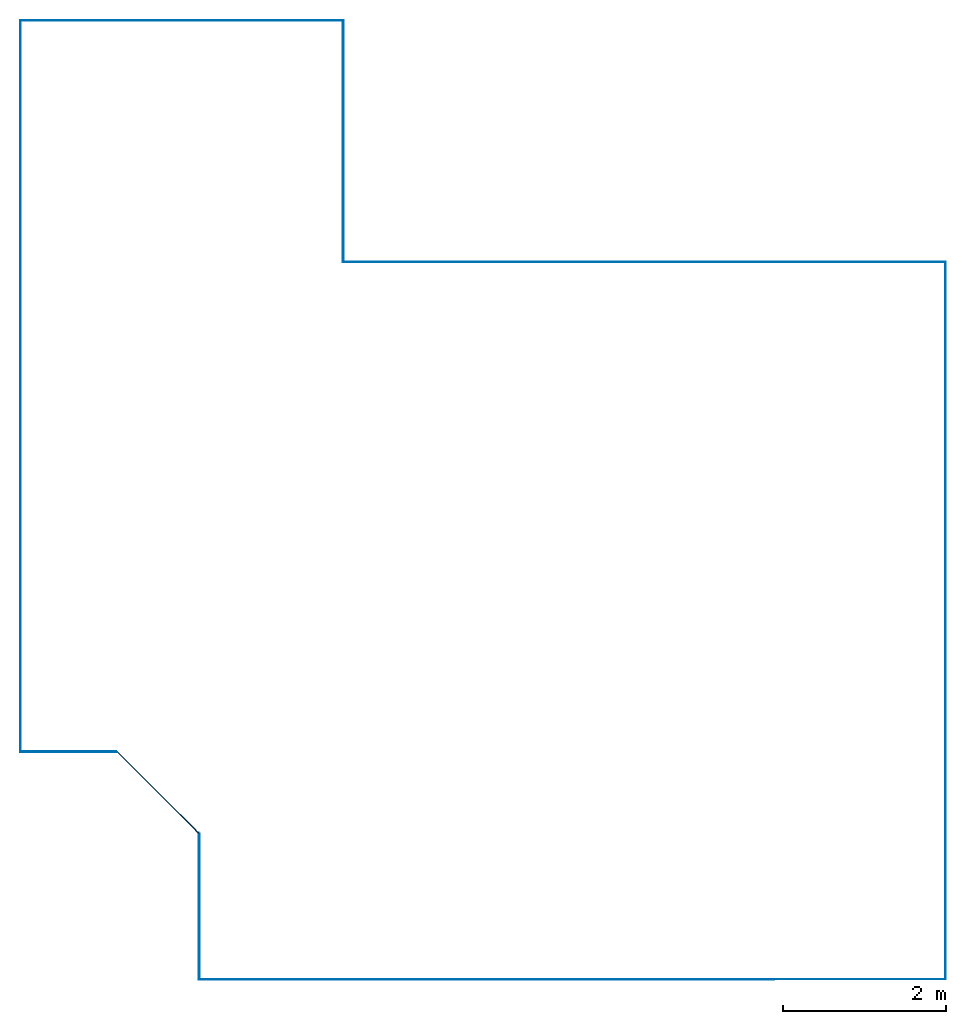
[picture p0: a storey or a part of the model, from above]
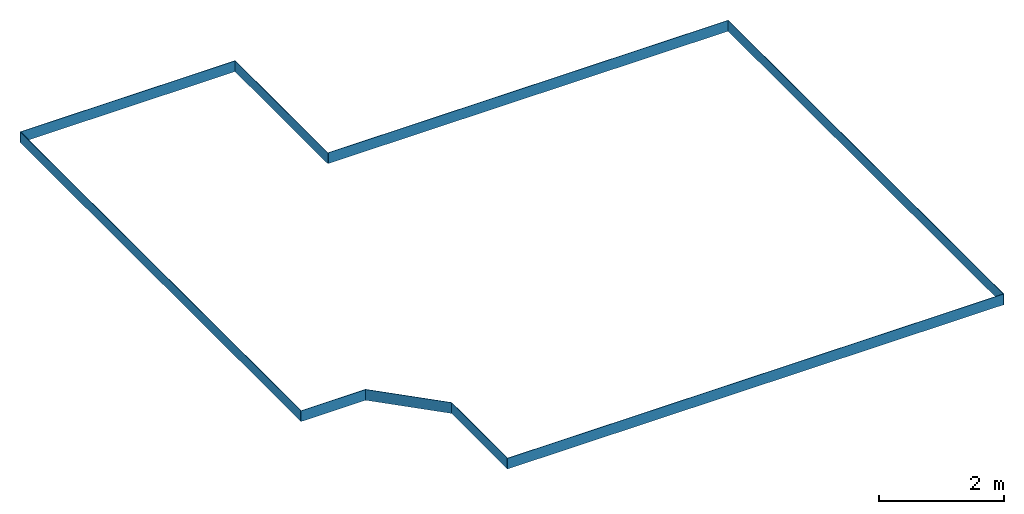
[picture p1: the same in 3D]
Properties of the parts of a building model (IFC2X3)

# File
Description: ViewDefinition [CoordinationView_V2.0], ExchangeRequirement [Architecture]
File name: Numéro du projet
Time: 2023-03-23T14:43:53+01:00
Written by: ODA SDAI 22.12
Made in: 23.0.11.19 - Exporter 23.0.11.19 - Interface utilisateur alternative 23.0.11.19

# IfcProject, Numéro du projet
LongName: Nom du projet; Phase: Etat du projet

# IfcSite, Default
RefLatitude: 48, 51, 23, 999633; RefLongitude: 2, 21, 3, 553905; RefElevation: 0 cm

# IfcBuilding
Pset_BuildingCommon - NumberOfStoreys: 4

# IfcBuildingStorey: Niveau:Ligne du Niveau (4)
Name | LongName | Elevation (cm)
0_Fondation | 0_Fondation | -98
-0.29_Dessous plancher | -0.29_Dessous plancher | -29
-0.08_Dessus plancher | -0.08_Dessus plancher | -8
2.57_Dessus dalle | 2.57_Dessus dalle | 257

# IfcBuildingElementProxy: 306233
In: 0_Fondation
Pset_ProvisionForVoid - Shape: Undefined; Depth: 114 cm

# IfcBuildingElementProxy: 306311
In: 0_Fondation
Pset_ProvisionForVoid - Shape: Undefined; Depth: 87 cm

# IfcBuildingElementProxy: 306359
In: 0_Fondation
Pset_ProvisionForVoid - Shape: Undefined; Depth: 67 cm

# IfcBuildingElementProxy: 306388
In: 0_Fondation
Pset_ProvisionForVoid - Shape: Undefined; Depth: 67 cm

# IfcBuildingElementProxy: 306447
In: 0_Fondation
Pset_ProvisionForVoid - Shape: Undefined; Depth: 346 cm

# IfcFooting: Semelle filante:Semelle 45 x 25 (9)
In: 0_Fondation
PredefinedType: STRIP_FOOTING; Material: Maçonnerie - Béton
Pset_QuantityTakeOff - Reference: Semelle filante:Semelle 45 x 25; sets with these values: 3
Name (Semelle filante:Semelle 45 x 25:...)
305962
305980
305998
306016
306030
306048
306066
306084
306102

# IfcFooting: Semelle filante:Semelle 45 x 25 refend (5)
In: 0_Fondation
PredefinedType: STRIP_FOOTING; Material: Maçonnerie - Béton
Pset_QuantityTakeOff - Reference: Semelle filante:Semelle 45 x 25 refend; sets with these values: 3
Name (Semelle filante:Semelle 45 x 25 refend:...)
306509
306563
306585
306607
306629

# IfcOpeningElement: Opening (19)
Name | In | Reference | sets with these values
Mur de base:Mur 20:300279 | -0.08_Dessus plancher | 1 Vantail - Droit blanc:140/90 | 2
Mur de base:Mur 20:300304 | -0.08_Dessus plancher | PF 1 Vantail - Droite blanc:80/210 | 2
Mur de base:Mur 20:300374 | -0.08_Dessus plancher | PF 2 Vantaux - Droits blanc:240/210 | 2
Mur de base:Mur 20:300374 | -0.08_Dessus plancher | PF 1 Vantail - Droite blanc:160/210 | 2
Mur de base:Mur 20:300374 | -0.08_Dessus plancher | PF 1 Vantail - Droite blanc:180/210 | 2
Mur de base:Mur 20:300423 | -0.08_Dessus plancher | PF 1 Vantail - Droite blanc:180/210 | 2
Mur de base:Mur 20:300423 | -0.08_Dessus plancher | 2 Vantaux coulissants - Droits blanc:140/80 | 2
2 x Mur de base:Mur 20:300475 | -0.08_Dessus plancher | 1 Vantail - Droit blanc:60/80 | 2
Mur de base:Mur 20:300475 | -0.08_Dessus plancher | 2 Vantaux coulissants - Droits blanc:140/80 | 2
Mur de base:Mur 20:300514 | -0.08_Dessus plancher | Porte d'entrée gris:90 x 215 cm | 2
Mur de base:Mur 20:300790 | -0.08_Dessus plancher | VLT17 Entrée:PP Avec moulures (0.90 m x 2.15 m) | 2
Sol:Plancher 12+4:302912:2 | 2.57_Dessus dalle | Sol:Plancher 12+4 | 2
Radier:Béton de propreté 5cm:306743:2 | 0_Fondation | Radier:Béton de propreté 5cm | 2
Mur de base:Mur 20:319389 | -0.08_Dessus plancher | PF 2 Vantaux - Droits blanc:240/210 | 2
Mur de base:Mur 20:319389 | -0.08_Dessus plancher | PF 1 Vantail - Droite blanc:160/210 | 2
Mur de base:Mur 20:319389 | -0.08_Dessus plancher | PF 1 Vantail - Droite blanc:180/210 | 2
Mur de base:Mur 20:300988 | -0.08_Dessus plancher
Mur de base:Mur 20:320650 | -0.08_Dessus plancher

# IfcSlab: Radier:Béton de propreté 5cm, Radier:Béton de propreté 5cm:306743:6
In: 0_Fondation
Type - PredefinedType: BASESLAB; Material: Maçonnerie - Béton(2) 5 cm
Type - Pset_SlabCommon - IsExternal: no
Pset_QuantityTakeOff - Reference: Radier:Béton de propreté 5cm; sets with these values: 2
Pset_SlabCommon - PitchAngle: 0 deg; Reference: Radier:Béton de propreté 5cm; LoadBearing: yes

# IfcSlab: Radier:Béton de propreté 5cm (5)
In: 0_Fondation
Type - PredefinedType: BASESLAB
Type - Pset_SlabCommon - IsExternal: no
Material: Maçonnerie - Béton(2) 5 cm
Pset_QuantityTakeOff - Reference: Radier:Béton de propreté 5cm; sets with these values: 2
Pset_SlabCommon - PitchAngle: 0 deg; Reference: Radier:Béton de propreté 5cm; LoadBearing: yes
Name (Radier:Béton de propreté 5cm:...)
306743
306743:2
306743:3
306743:4
306743:5

# IfcSlab: Sol:Plancher 12+4, Sol:Plancher 12+4:302912
In: 2.57_Dessus dalle
Type - PredefinedType: FLOOR; Material: Maçonnerie - Béton dalle 16 cm
Type - Pset_SlabCommon - IsExternal: no
Pset_QuantityTakeOff - Reference: Sol:Plancher 12+4; sets with these values: 2
Pset_SlabCommon - LoadBearing: no; PitchAngle: 0 deg; Reference: Sol:Plancher 12+4

# IfcSlab: Sol:Plancher 4+12+5, Sol:Plancher 4+12+5:302016
In: -0.08_Dessus plancher
Type - PredefinedType: FLOOR; Material: Maçonnerie - Béton 21 cm
Type - Pset_SlabCommon - IsExternal: no
Pset_QuantityTakeOff - Reference: Sol:Plancher 4+12+5; sets with these values: 2
Pset_SlabCommon - LoadBearing: no; Reference: Sol:Plancher 4+12+5; PitchAngle: 0 deg

# IfcWall: Mur de base:Mur 20 (10)
In: -0.08_Dessus plancher
Type - PredefinedType: STANDARD; Material: Maçonnerie - Béton 20 cm
Type - Pset_WallCommon - IsExternal: yes
Pset_QuantityTakeOff - Reference: Mur de base:Mur 20; sets with these values: 2
Pset_WallCommon - Reference: Mur de base:Mur 20; LoadBearing: no; ExtendToStructure: no
Name (Mur de base:Mur 20:...)
370322
370325
370326
370327
370328
370329
370330
370331
370332
370333

# IfcWall: Mur de base:Mur de soubassement (13)
Type - PredefinedType: STANDARD; Material: Protection humidité 1 cm, Blocs de maçonnerie en béton 20 cm
Type - Pset_WallCommon - IsExternal: yes; ThermalTransmittance: 6.15226 kg/K/s3
Pset_QuantityTakeOff - Reference: Mur de base:Mur de soubassement; sets with these values: 2
Pset_WallCommon - LoadBearing: no; Reference: Mur de base:Mur de soubassement; ExtendToStructure: no
Name (Mur de base:Mur de soubassement:...) | In
305063 | 0_Fondation
305104 | 0_Fondation
305104 | -0.29_Dessous plancher
305176 | 0_Fondation
305253 | 0_Fondation
305253 | -0.29_Dessous plancher
305323 | 0_Fondation
305364 | 0_Fondation
305364 | -0.29_Dessous plancher
305403 | 0_Fondation
305420 | 0_Fondation
305466 | 0_Fondation
305466 | -0.29_Dessous plancher

# IfcWallStandardCase: Mur de base:Mur 20 (12)
In: -0.08_Dessus plancher
Type - PredefinedType: STANDARD; Material: Maçonnerie - Béton 20 cm
Type - Pset_WallCommon - IsExternal: yes
Pset_QuantityTakeOff - Reference: Mur de base:Mur 20; sets with these values: 2
Pset_WallCommon - Reference: Mur de base:Mur 20; LoadBearing: no
Name (Mur de base:Mur 20:...) | ExtendToStructure
300279 | yes
300304 | yes
300374 | yes
300423 | yes
300475 | yes
300514 | yes
300790 | yes
300898 | yes
300988 | yes
319389 | yes
320650 | yes
370335 | no

# IfcWallStandardCase: Mur de base:Mur de soubassement (5)
In: -0.29_Dessous plancher
Type - PredefinedType: STANDARD; Material: Protection humidité 1 cm, Blocs de maçonnerie en béton 20 cm
Type - Pset_WallCommon - IsExternal: yes; ThermalTransmittance: 6.15226 kg/K/s3
Pset_QuantityTakeOff - Reference: Mur de base:Mur de soubassement; sets with these values: 2
Pset_WallCommon - LoadBearing: no; Reference: Mur de base:Mur de soubassement; ExtendToStructure: no
Name (Mur de base:Mur de soubassement:...)
305063
305176
305323
305403
305420

# IfcWallStandardCase: Mur de base:Mur de soubassement refend (5)
In: 0_Fondation
Type - PredefinedType: STANDARD; Material: Blocs de maçonnerie en béton 20 cm
Type - Pset_WallCommon - IsExternal: yes; ThermalTransmittance: 6.5 kg/K/s3
Pset_QuantityTakeOff - Reference: Mur de base:Mur de soubassement refend; sets with these values: 2
Pset_WallCommon - LoadBearing: no; ExtendToStructure: no; Reference: Mur de base:Mur de soubassement refend
Name (Mur de base:Mur de soubassement refend:...)
306230
306310
306357
306387
306446

# IfcWallStandardCase: Mur de base:Mur refend 22 (5)
In: -0.08_Dessus plancher
Type - PredefinedType: STANDARD; Material: Plâtre 1 cm, Mur par défaut 20 cm, Plâtre 1 cm
Type - Pset_WallCommon - IsExternal: yes; ThermalTransmittance: 25.5 kg/K/s3
Pset_QuantityTakeOff - Reference: Mur de base:Mur refend 22; sets with these values: 2
Pset_WallCommon - ExtendToStructure: yes; LoadBearing: no; Reference: Mur de base:Mur refend 22
Name (Mur de base:Mur refend 22:...)
301366
301477
301562
301671
301788
